VERSION 5.7 ;
  NOWIREEXTENSIONATPIN ON ;
  DIVIDERCHAR "/" ;
  BUSBITCHARS "[]" ;
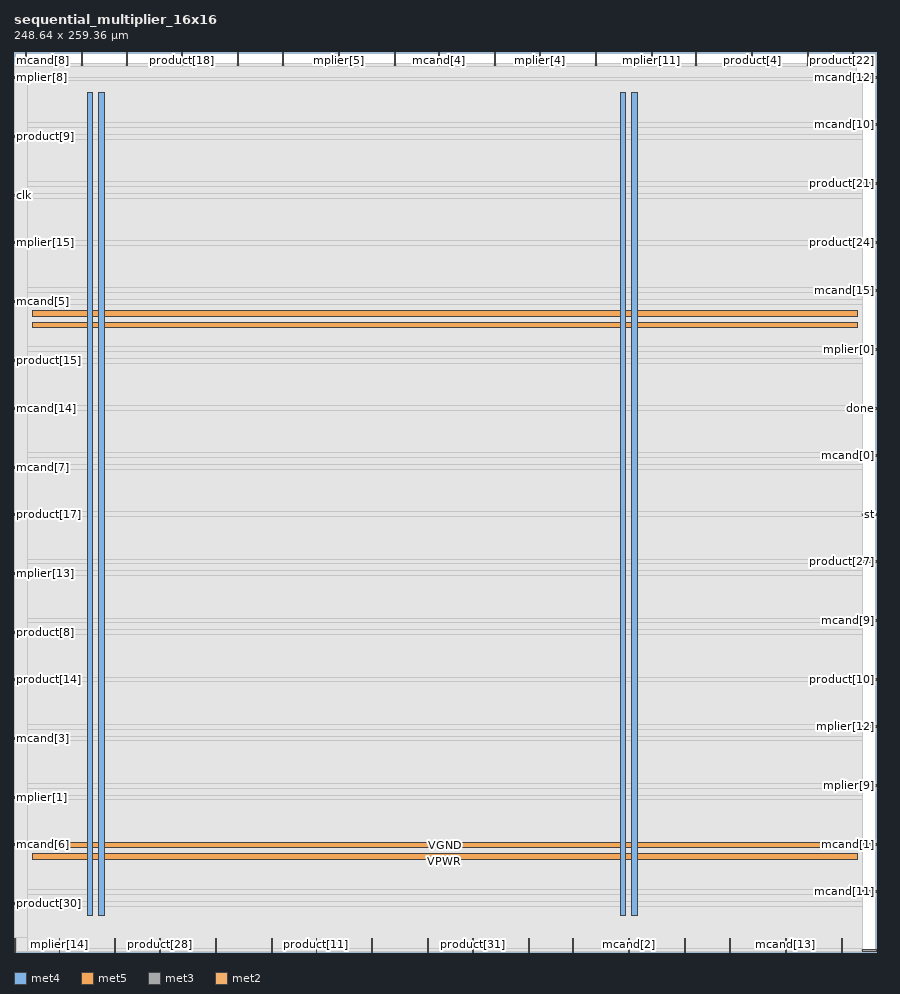
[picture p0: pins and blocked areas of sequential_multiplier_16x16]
MACRO sequential_multiplier_16x16
  CLASS BLOCK ;
  FOREIGN sequential_multiplier_16x16 ;
  ORIGIN 0.000 0.000 ;
  SIZE 248.640 BY 259.360 ;
  PIN VGND
    DIRECTION INOUT ;
    USE GROUND ;
    PORT
      LAYER met4 ;
        RECT 24.340 10.640 25.940 247.760 ;
    END
    PORT
      LAYER met4 ;
        RECT 177.940 10.640 179.540 247.760 ;
    END
    PORT
      LAYER met5 ;
        RECT 5.280 30.030 243.120 31.630 ;
    END
    PORT
      LAYER met5 ;
        RECT 5.280 183.210 243.120 184.810 ;
    END
  END VGND
  PIN VPWR
    DIRECTION INOUT ;
    USE POWER ;
    PORT
      LAYER met4 ;
        RECT 21.040 10.640 22.640 247.760 ;
    END
    PORT
      LAYER met4 ;
        RECT 174.640 10.640 176.240 247.760 ;
    END
    PORT
      LAYER met5 ;
        RECT 5.280 26.730 243.120 28.330 ;
    END
    PORT
      LAYER met5 ;
        RECT 5.280 179.910 243.120 181.510 ;
    END
  END VPWR
  PIN clk
    DIRECTION INPUT ;
    USE SIGNAL ;
    ANTENNAGATEAREA 0.852000 ;
    PORT
      LAYER met3 ;
        RECT 0.000 217.640 4.000 218.240 ;
    END
  END clk
  PIN done
    DIRECTION OUTPUT TRISTATE ;
    USE SIGNAL ;
    ANTENNADIFFAREA 0.795200 ;
    PORT
      LAYER met3 ;
        RECT 244.640 156.440 248.640 157.040 ;
    END
  END done
  PIN mcand[0]
    DIRECTION INPUT ;
    USE SIGNAL ;
    ANTENNAGATEAREA 0.213000 ;
    PORT
      LAYER met3 ;
        RECT 244.640 142.840 248.640 143.440 ;
    END
  END mcand[0]
  PIN mcand[10]
    DIRECTION INPUT ;
    USE SIGNAL ;
    ANTENNAGATEAREA 0.213000 ;
    PORT
      LAYER met3 ;
        RECT 244.640 238.040 248.640 238.640 ;
    END
  END mcand[10]
  PIN mcand[11]
    DIRECTION INPUT ;
    USE SIGNAL ;
    ANTENNAGATEAREA 0.159000 ;
    PORT
      LAYER met3 ;
        RECT 244.640 17.040 248.640 17.640 ;
    END
  END mcand[11]
  PIN mcand[12]
    DIRECTION INPUT ;
    USE SIGNAL ;
    ANTENNAGATEAREA 0.213000 ;
    PORT
      LAYER met3 ;
        RECT 244.640 251.640 248.640 252.240 ;
    END
  END mcand[12]
  PIN mcand[13]
    DIRECTION INPUT ;
    USE SIGNAL ;
    ANTENNAGATEAREA 0.126000 ;
    PORT
      LAYER met2 ;
        RECT 222.270 0.000 222.550 4.000 ;
    END
  END mcand[13]
  PIN mcand[14]
    DIRECTION INPUT ;
    USE SIGNAL ;
    ANTENNAGATEAREA 0.213000 ;
    PORT
      LAYER met3 ;
        RECT 0.000 156.440 4.000 157.040 ;
    END
  END mcand[14]
  PIN mcand[15]
    DIRECTION INPUT ;
    USE SIGNAL ;
    ANTENNAGATEAREA 0.213000 ;
    PORT
      LAYER met3 ;
        RECT 244.640 190.440 248.640 191.040 ;
    END
  END mcand[15]
  PIN mcand[1]
    DIRECTION INPUT ;
    USE SIGNAL ;
    ANTENNAGATEAREA 0.213000 ;
    PORT
      LAYER met3 ;
        RECT 244.640 30.640 248.640 31.240 ;
    END
  END mcand[1]
  PIN mcand[2]
    DIRECTION INPUT ;
    USE SIGNAL ;
    ANTENNAGATEAREA 0.213000 ;
    PORT
      LAYER met2 ;
        RECT 177.190 0.000 177.470 4.000 ;
    END
  END mcand[2]
  PIN mcand[3]
    DIRECTION INPUT ;
    USE SIGNAL ;
    ANTENNAGATEAREA 0.213000 ;
    PORT
      LAYER met3 ;
        RECT 0.000 61.240 4.000 61.840 ;
    END
  END mcand[3]
  PIN mcand[4]
    DIRECTION INPUT ;
    USE SIGNAL ;
    ANTENNAGATEAREA 0.196500 ;
    PORT
      LAYER met2 ;
        RECT 122.450 255.360 122.730 259.360 ;
    END
  END mcand[4]
  PIN mcand[5]
    DIRECTION INPUT ;
    USE SIGNAL ;
    ANTENNAGATEAREA 0.196500 ;
    PORT
      LAYER met3 ;
        RECT 0.000 187.040 4.000 187.640 ;
    END
  END mcand[5]
  PIN mcand[6]
    DIRECTION INPUT ;
    USE SIGNAL ;
    ANTENNAGATEAREA 0.159000 ;
    PORT
      LAYER met3 ;
        RECT 0.000 30.640 4.000 31.240 ;
    END
  END mcand[6]
  PIN mcand[7]
    DIRECTION INPUT ;
    USE SIGNAL ;
    ANTENNAGATEAREA 0.196500 ;
    PORT
      LAYER met3 ;
        RECT 0.000 139.440 4.000 140.040 ;
    END
  END mcand[7]
  PIN mcand[8]
    DIRECTION INPUT ;
    USE SIGNAL ;
    ANTENNAGATEAREA 0.159000 ;
    PORT
      LAYER met2 ;
        RECT 3.310 255.360 3.590 259.360 ;
    END
  END mcand[8]
  PIN mcand[9]
    DIRECTION INPUT ;
    USE SIGNAL ;
    ANTENNAGATEAREA 0.159000 ;
    PORT
      LAYER met3 ;
        RECT 244.640 95.240 248.640 95.840 ;
    END
  END mcand[9]
  PIN mplier[0]
    DIRECTION INPUT ;
    USE SIGNAL ;
    ANTENNAGATEAREA 0.126000 ;
    PORT
      LAYER met3 ;
        RECT 244.640 173.440 248.640 174.040 ;
    END
  END mplier[0]
  PIN mplier[10]
    DIRECTION INPUT ;
    USE SIGNAL ;
    ANTENNAGATEAREA 0.196500 ;
    PORT
      LAYER met2 ;
        RECT 58.050 0.000 58.330 4.000 ;
    END
  END mplier[10]
  PIN mplier[11]
    DIRECTION INPUT ;
    USE SIGNAL ;
    ANTENNAGATEAREA 0.196500 ;
    PORT
      LAYER met2 ;
        RECT 183.630 255.360 183.910 259.360 ;
    END
  END mplier[11]
  PIN mplier[12]
    DIRECTION INPUT ;
    USE SIGNAL ;
    ANTENNAGATEAREA 0.196500 ;
    PORT
      LAYER met3 ;
        RECT 244.640 64.640 248.640 65.240 ;
    END
  END mplier[12]
  PIN mplier[13]
    DIRECTION INPUT ;
    USE SIGNAL ;
    ANTENNAGATEAREA 0.196500 ;
    PORT
      LAYER met3 ;
        RECT 0.000 108.840 4.000 109.440 ;
    END
  END mplier[13]
  PIN mplier[14]
    DIRECTION INPUT ;
    USE SIGNAL ;
    ANTENNAGATEAREA 0.196500 ;
    PORT
      LAYER met2 ;
        RECT 12.970 0.000 13.250 4.000 ;
    END
  END mplier[14]
  PIN mplier[15]
    DIRECTION INPUT ;
    USE SIGNAL ;
    ANTENNAGATEAREA 0.196500 ;
    PORT
      LAYER met3 ;
        RECT 0.000 204.040 4.000 204.640 ;
    END
  END mplier[15]
  PIN mplier[1]
    DIRECTION INPUT ;
    USE SIGNAL ;
    ANTENNAGATEAREA 0.196500 ;
    PORT
      LAYER met3 ;
        RECT 0.000 44.240 4.000 44.840 ;
    END
  END mplier[1]
  PIN mplier[2]
    DIRECTION INPUT ;
    USE SIGNAL ;
    ANTENNAGATEAREA 0.196500 ;
    PORT
      LAYER met2 ;
        RECT 238.370 0.000 238.650 4.000 ;
    END
  END mplier[2]
  PIN mplier[3]
    DIRECTION INPUT ;
    USE SIGNAL ;
    ANTENNAGATEAREA 0.213000 ;
    PORT
      LAYER met2 ;
        RECT 206.170 0.000 206.450 4.000 ;
    END
  END mplier[3]
  PIN mplier[4]
    DIRECTION INPUT ;
    USE SIGNAL ;
    ANTENNAGATEAREA 0.196500 ;
    PORT
      LAYER met2 ;
        RECT 151.430 255.360 151.710 259.360 ;
    END
  END mplier[4]
  PIN mplier[5]
    DIRECTION INPUT ;
    USE SIGNAL ;
    ANTENNAGATEAREA 0.196500 ;
    PORT
      LAYER met2 ;
        RECT 93.470 255.360 93.750 259.360 ;
    END
  END mplier[5]
  PIN mplier[6]
    DIRECTION INPUT ;
    USE SIGNAL ;
    ANTENNAGATEAREA 0.196500 ;
    PORT
      LAYER met2 ;
        RECT 193.290 0.000 193.570 4.000 ;
    END
  END mplier[6]
  PIN mplier[7]
    DIRECTION INPUT ;
    USE SIGNAL ;
    ANTENNAGATEAREA 0.126000 ;
    PORT
      LAYER met2 ;
        RECT 138.550 255.360 138.830 259.360 ;
    END
  END mplier[7]
  PIN mplier[8]
    DIRECTION INPUT ;
    USE SIGNAL ;
    ANTENNAGATEAREA 0.196500 ;
    PORT
      LAYER met3 ;
        RECT 0.000 251.640 4.000 252.240 ;
    END
  END mplier[8]
  PIN mplier[9]
    DIRECTION INPUT ;
    USE SIGNAL ;
    ANTENNAGATEAREA 0.126000 ;
    PORT
      LAYER met3 ;
        RECT 244.640 47.640 248.640 48.240 ;
    END
  END mplier[9]
  PIN product[0]
    DIRECTION OUTPUT TRISTATE ;
    USE SIGNAL ;
    ANTENNADIFFAREA 0.795200 ;
    PORT
      LAYER met2 ;
        RECT 148.210 0.000 148.490 4.000 ;
    END
  END product[0]
  PIN product[10]
    DIRECTION OUTPUT TRISTATE ;
    USE SIGNAL ;
    ANTENNADIFFAREA 0.795200 ;
    PORT
      LAYER met3 ;
        RECT 244.640 78.240 248.640 78.840 ;
    END
  END product[10]
  PIN product[11]
    DIRECTION OUTPUT TRISTATE ;
    USE SIGNAL ;
    ANTENNADIFFAREA 0.795200 ;
    PORT
      LAYER met2 ;
        RECT 87.030 0.000 87.310 4.000 ;
    END
  END product[11]
  PIN product[12]
    DIRECTION OUTPUT TRISTATE ;
    USE SIGNAL ;
    ANTENNADIFFAREA 0.795200 ;
    PORT
      LAYER met2 ;
        RECT 196.510 255.360 196.790 259.360 ;
    END
  END product[12]
  PIN product[13]
    DIRECTION OUTPUT TRISTATE ;
    USE SIGNAL ;
    ANTENNADIFFAREA 0.795200 ;
    PORT
      LAYER met2 ;
        RECT 19.410 255.360 19.690 259.360 ;
    END
  END product[13]
  PIN product[14]
    DIRECTION OUTPUT TRISTATE ;
    USE SIGNAL ;
    ANTENNADIFFAREA 0.795200 ;
    PORT
      LAYER met3 ;
        RECT 0.000 78.240 4.000 78.840 ;
    END
  END product[14]
  PIN product[15]
    DIRECTION OUTPUT TRISTATE ;
    USE SIGNAL ;
    ANTENNADIFFAREA 0.795200 ;
    PORT
      LAYER met3 ;
        RECT 0.000 170.040 4.000 170.640 ;
    END
  END product[15]
  PIN product[16]
    DIRECTION OUTPUT TRISTATE ;
    USE SIGNAL ;
    ANTENNADIFFAREA 0.795200 ;
    PORT
      LAYER met2 ;
        RECT 167.530 255.360 167.810 259.360 ;
    END
  END product[16]
  PIN product[17]
    DIRECTION OUTPUT TRISTATE ;
    USE SIGNAL ;
    ANTENNADIFFAREA 0.795200 ;
    PORT
      LAYER met3 ;
        RECT 0.000 125.840 4.000 126.440 ;
    END
  END product[17]
  PIN product[18]
    DIRECTION OUTPUT TRISTATE ;
    USE SIGNAL ;
    ANTENNADIFFAREA 0.795200 ;
    PORT
      LAYER met2 ;
        RECT 48.390 255.360 48.670 259.360 ;
    END
  END product[18]
  PIN product[19]
    DIRECTION OUTPUT TRISTATE ;
    USE SIGNAL ;
    ANTENNADIFFAREA 0.795200 ;
    PORT
      LAYER met2 ;
        RECT 109.570 255.360 109.850 259.360 ;
    END
  END product[19]
  PIN product[1]
    DIRECTION OUTPUT TRISTATE ;
    USE SIGNAL ;
    ANTENNADIFFAREA 0.795200 ;
    PORT
      LAYER met2 ;
        RECT 29.070 0.000 29.350 4.000 ;
    END
  END product[1]
  PIN product[20]
    DIRECTION OUTPUT TRISTATE ;
    USE SIGNAL ;
    ANTENNADIFFAREA 0.795200 ;
    PORT
      LAYER met2 ;
        RECT 0.090 0.000 0.370 4.000 ;
    END
  END product[20]
  PIN product[21]
    DIRECTION OUTPUT TRISTATE ;
    USE SIGNAL ;
    ANTENNADIFFAREA 0.795200 ;
    PORT
      LAYER met3 ;
        RECT 244.640 221.040 248.640 221.640 ;
    END
  END product[21]
  PIN product[22]
    DIRECTION OUTPUT TRISTATE ;
    USE SIGNAL ;
    ANTENNADIFFAREA 0.795200 ;
    PORT
      LAYER met2 ;
        RECT 241.590 255.360 241.870 259.360 ;
    END
  END product[22]
  PIN product[23]
    DIRECTION OUTPUT TRISTATE ;
    USE SIGNAL ;
    ANTENNADIFFAREA 0.795200 ;
    PORT
      LAYER met2 ;
        RECT 103.130 0.000 103.410 4.000 ;
    END
  END product[23]
  PIN product[24]
    DIRECTION OUTPUT TRISTATE ;
    USE SIGNAL ;
    ANTENNADIFFAREA 0.795200 ;
    PORT
      LAYER met3 ;
        RECT 244.640 204.040 248.640 204.640 ;
    END
  END product[24]
  PIN product[25]
    DIRECTION OUTPUT TRISTATE ;
    USE SIGNAL ;
    ANTENNADIFFAREA 0.795200 ;
    PORT
      LAYER met3 ;
        RECT 244.640 0.040 248.640 0.640 ;
    END
  END product[25]
  PIN product[26]
    DIRECTION OUTPUT TRISTATE ;
    USE SIGNAL ;
    ANTENNADIFFAREA 0.795200 ;
    PORT
      LAYER met2 ;
        RECT 77.370 255.360 77.650 259.360 ;
    END
  END product[26]
  PIN product[27]
    DIRECTION OUTPUT TRISTATE ;
    USE SIGNAL ;
    ANTENNADIFFAREA 0.795200 ;
    PORT
      LAYER met3 ;
        RECT 244.640 112.240 248.640 112.840 ;
    END
  END product[27]
  PIN product[28]
    DIRECTION OUTPUT TRISTATE ;
    USE SIGNAL ;
    ANTENNADIFFAREA 0.795200 ;
    PORT
      LAYER met2 ;
        RECT 41.950 0.000 42.230 4.000 ;
    END
  END product[28]
  PIN product[29]
    DIRECTION OUTPUT TRISTATE ;
    USE SIGNAL ;
    ANTENNADIFFAREA 0.795200 ;
    PORT
      LAYER met2 ;
        RECT 74.150 0.000 74.430 4.000 ;
    END
  END product[29]
  PIN product[2]
    DIRECTION OUTPUT TRISTATE ;
    USE SIGNAL ;
    ANTENNADIFFAREA 0.795200 ;
    PORT
      LAYER met2 ;
        RECT 119.230 0.000 119.510 4.000 ;
    END
  END product[2]
  PIN product[30]
    DIRECTION OUTPUT TRISTATE ;
    USE SIGNAL ;
    ANTENNADIFFAREA 0.795200 ;
    PORT
      LAYER met3 ;
        RECT 0.000 13.640 4.000 14.240 ;
    END
  END product[30]
  PIN product[31]
    DIRECTION OUTPUT TRISTATE ;
    USE SIGNAL ;
    ANTENNADIFFAREA 0.795200 ;
    PORT
      LAYER met2 ;
        RECT 132.110 0.000 132.390 4.000 ;
    END
  END product[31]
  PIN product[3]
    DIRECTION OUTPUT TRISTATE ;
    USE SIGNAL ;
    ANTENNADIFFAREA 0.795200 ;
    PORT
      LAYER met2 ;
        RECT 228.710 255.360 228.990 259.360 ;
    END
  END product[3]
  PIN product[4]
    DIRECTION OUTPUT TRISTATE ;
    USE SIGNAL ;
    ANTENNADIFFAREA 0.795200 ;
    PORT
      LAYER met2 ;
        RECT 212.610 255.360 212.890 259.360 ;
    END
  END product[4]
  PIN product[5]
    DIRECTION OUTPUT TRISTATE ;
    USE SIGNAL ;
    ANTENNADIFFAREA 0.795200 ;
    PORT
      LAYER met2 ;
        RECT 32.290 255.360 32.570 259.360 ;
    END
  END product[5]
  PIN product[6]
    DIRECTION OUTPUT TRISTATE ;
    USE SIGNAL ;
    ANTENNADIFFAREA 0.445500 ;
    PORT
      LAYER met2 ;
        RECT 64.490 255.360 64.770 259.360 ;
    END
  END product[6]
  PIN product[7]
    DIRECTION OUTPUT TRISTATE ;
    USE SIGNAL ;
    ANTENNADIFFAREA 0.795200 ;
    PORT
      LAYER met2 ;
        RECT 161.090 0.000 161.370 4.000 ;
    END
  END product[7]
  PIN product[8]
    DIRECTION OUTPUT TRISTATE ;
    USE SIGNAL ;
    ANTENNADIFFAREA 0.795200 ;
    PORT
      LAYER met3 ;
        RECT 0.000 91.840 4.000 92.440 ;
    END
  END product[8]
  PIN product[9]
    DIRECTION OUTPUT TRISTATE ;
    USE SIGNAL ;
    ANTENNADIFFAREA 0.795200 ;
    PORT
      LAYER met3 ;
        RECT 0.000 234.640 4.000 235.240 ;
    END
  END product[9]
  PIN st
    DIRECTION INPUT ;
    USE SIGNAL ;
    ANTENNAGATEAREA 0.159000 ;
    PORT
      LAYER met3 ;
        RECT 244.640 125.840 248.640 126.440 ;
    END
  END st
  OBS
      LAYER li1 ;
        RECT 5.520 10.795 242.880 247.605 ;
      LAYER met1 ;
        RECT 0.070 9.220 242.880 248.160 ;
      LAYER met2 ;
        RECT 0.100 255.080 3.030 256.090 ;
        RECT 3.870 255.080 19.130 256.090 ;
        RECT 19.970 255.080 32.010 256.090 ;
        RECT 32.850 255.080 48.110 256.090 ;
        RECT 48.950 255.080 64.210 256.090 ;
        RECT 65.050 255.080 77.090 256.090 ;
        RECT 77.930 255.080 93.190 256.090 ;
        RECT 94.030 255.080 109.290 256.090 ;
        RECT 110.130 255.080 122.170 256.090 ;
        RECT 123.010 255.080 138.270 256.090 ;
        RECT 139.110 255.080 151.150 256.090 ;
        RECT 151.990 255.080 167.250 256.090 ;
        RECT 168.090 255.080 183.350 256.090 ;
        RECT 184.190 255.080 196.230 256.090 ;
        RECT 197.070 255.080 212.330 256.090 ;
        RECT 213.170 255.080 228.430 256.090 ;
        RECT 229.270 255.080 241.310 256.090 ;
        RECT 242.150 255.080 242.790 256.090 ;
        RECT 0.100 4.280 242.790 255.080 ;
        RECT 0.650 0.155 12.690 4.280 ;
        RECT 13.530 0.155 28.790 4.280 ;
        RECT 29.630 0.155 41.670 4.280 ;
        RECT 42.510 0.155 57.770 4.280 ;
        RECT 58.610 0.155 73.870 4.280 ;
        RECT 74.710 0.155 86.750 4.280 ;
        RECT 87.590 0.155 102.850 4.280 ;
        RECT 103.690 0.155 118.950 4.280 ;
        RECT 119.790 0.155 131.830 4.280 ;
        RECT 132.670 0.155 147.930 4.280 ;
        RECT 148.770 0.155 160.810 4.280 ;
        RECT 161.650 0.155 176.910 4.280 ;
        RECT 177.750 0.155 193.010 4.280 ;
        RECT 193.850 0.155 205.890 4.280 ;
        RECT 206.730 0.155 221.990 4.280 ;
        RECT 222.830 0.155 238.090 4.280 ;
        RECT 238.930 0.155 242.790 4.280 ;
      LAYER met3 ;
        RECT 4.400 251.240 244.240 252.105 ;
        RECT 3.990 239.040 244.640 251.240 ;
        RECT 3.990 237.640 244.240 239.040 ;
        RECT 3.990 235.640 244.640 237.640 ;
        RECT 4.400 234.240 244.640 235.640 ;
        RECT 3.990 222.040 244.640 234.240 ;
        RECT 3.990 220.640 244.240 222.040 ;
        RECT 3.990 218.640 244.640 220.640 ;
        RECT 4.400 217.240 244.640 218.640 ;
        RECT 3.990 205.040 244.640 217.240 ;
        RECT 4.400 203.640 244.240 205.040 ;
        RECT 3.990 191.440 244.640 203.640 ;
        RECT 3.990 190.040 244.240 191.440 ;
        RECT 3.990 188.040 244.640 190.040 ;
        RECT 4.400 186.640 244.640 188.040 ;
        RECT 3.990 174.440 244.640 186.640 ;
        RECT 3.990 173.040 244.240 174.440 ;
        RECT 3.990 171.040 244.640 173.040 ;
        RECT 4.400 169.640 244.640 171.040 ;
        RECT 3.990 157.440 244.640 169.640 ;
        RECT 4.400 156.040 244.240 157.440 ;
        RECT 3.990 143.840 244.640 156.040 ;
        RECT 3.990 142.440 244.240 143.840 ;
        RECT 3.990 140.440 244.640 142.440 ;
        RECT 4.400 139.040 244.640 140.440 ;
        RECT 3.990 126.840 244.640 139.040 ;
        RECT 4.400 125.440 244.240 126.840 ;
        RECT 3.990 113.240 244.640 125.440 ;
        RECT 3.990 111.840 244.240 113.240 ;
        RECT 3.990 109.840 244.640 111.840 ;
        RECT 4.400 108.440 244.640 109.840 ;
        RECT 3.990 96.240 244.640 108.440 ;
        RECT 3.990 94.840 244.240 96.240 ;
        RECT 3.990 92.840 244.640 94.840 ;
        RECT 4.400 91.440 244.640 92.840 ;
        RECT 3.990 79.240 244.640 91.440 ;
        RECT 4.400 77.840 244.240 79.240 ;
        RECT 3.990 65.640 244.640 77.840 ;
        RECT 3.990 64.240 244.240 65.640 ;
        RECT 3.990 62.240 244.640 64.240 ;
        RECT 4.400 60.840 244.640 62.240 ;
        RECT 3.990 48.640 244.640 60.840 ;
        RECT 3.990 47.240 244.240 48.640 ;
        RECT 3.990 45.240 244.640 47.240 ;
        RECT 4.400 43.840 244.640 45.240 ;
        RECT 3.990 31.640 244.640 43.840 ;
        RECT 4.400 30.240 244.240 31.640 ;
        RECT 3.990 18.040 244.640 30.240 ;
        RECT 3.990 16.640 244.240 18.040 ;
        RECT 3.990 14.640 244.640 16.640 ;
        RECT 4.400 13.240 244.640 14.640 ;
        RECT 3.990 1.040 244.640 13.240 ;
        RECT 3.990 0.175 244.240 1.040 ;
  END
END sequential_multiplier_16x16
END LIBRARY

